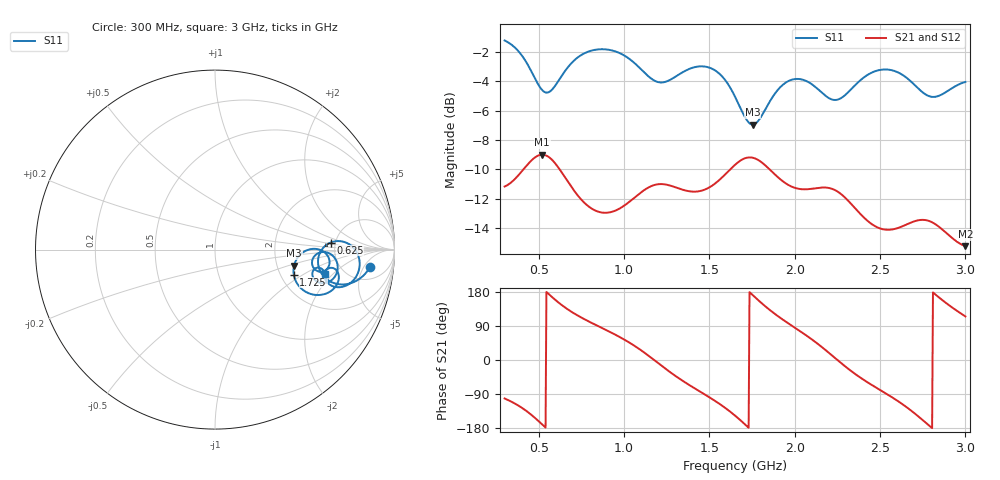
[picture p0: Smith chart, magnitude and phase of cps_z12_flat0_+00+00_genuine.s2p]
! cps_z12_flat0_+00+00_genuine
! simulated by sim/fixtures_fdtd.py (S12 = S21, S22 not computed)
# HZ S RI R 50
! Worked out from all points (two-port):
!   541 points, 300 MHz to 3 GHz, reference 50 ohm
!   highest |S21| = -8.99 dB at 520 MHz (marker M1); lowest = -15.2 dB at 3 GHz (marker M2)
!   |S21| within 3 dB of the highest: start of sweep to 745.1 MHz; 1.053 GHz to 2.302 GHz (1.249 GHz wide, 74.5 % of centre)
!   lowest |S11| = -6.9 dB at 1.755 GHz (marker M3), VSWR 2.63, Z = 124 - j28 ohm
!   |S11| at or under -10 dB: nowhere
!   |S22| runs from - to - dB; largest |S21 - S12| = 0
!   S11 on the Smith chart (normalised r, x): 300 MHz: 9, -7; 625 MHz: 4.55, +0.61; 1.725 GHz: 2.36, -0.84; 3 GHz: 3.58, -1.63
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3e8  0.8627 -0.0984  -0.0554 -0.2712  -0.0554 -0.2712  0 0
4.25e8  0.7096 -0.1943  -0.2234 -0.2344  -0.2234 -0.2344  0 0
5.2e8  0.5797 -0.1037  -0.3497 -0.0619  -0.3497 -0.0619  0 0
6.25e8  0.6443 0.0392  -0.2681 0.1652  -0.2681 0.1652  0 0
7.5e8  0.7752 0.00595  -0.093 0.2316  -0.093 0.2316  0 0
8.85e8  0.8031 -0.1079  0.0341 0.2227  0.0341 0.2227  0 0
1.025e9  0.7288 -0.2013  0.1645 0.1802  0.1645 0.1802  0 0
1.2e9  0.6094 -0.146  0.2788 -0.0405  0.2788 -0.0405  0 0
1.305e9  0.6481 -0.1015  0.1998 -0.1883  0.1998 -0.1883  0 0
1.42e9  0.69 -0.1488  0.0619 -0.2586  0.0619 -0.2586  0 0
1.555e9  0.6273 -0.2414  -0.1203 -0.2641  -0.1203 -0.2641  0 0
1.65e9  0.5071 -0.236  -0.2738 -0.1803  -0.2738 -0.1803  0 0
1.725e9  0.439 -0.1397  -0.3466 -0.0197  -0.3466 -0.0197  0 0
1.755e9  0.4404 -0.09  -0.342 0.056  -0.342 0.056  0 0
1.895e9  0.5841 -0.000969  -0.1401 0.2652  -0.1401 0.2652  0 0
2.1e9  0.6044 -0.1205  0.158 0.2212  0.158 0.2212  0 0
2.26e9  0.5465 -0.0474  0.2633 -0.017  0.2633 -0.017  0 0
2.38e9  0.6322 -0.019  0.1587 -0.1591  0.1587 -0.1591  0 0
2.55e9  0.6788 -0.1288  -0.00943 -0.197  -0.00943 -0.197  0 0
2.67e9  0.6101 -0.1866  -0.1315 -0.1603  -0.1315 -0.1603  0 0
2.78e9  0.544 -0.1475  -0.2088 -0.0362  -0.2088 -0.0362  0 0
3e9  0.6121 -0.1381  -0.0732 0.1573  -0.0732 0.1573  0 0
